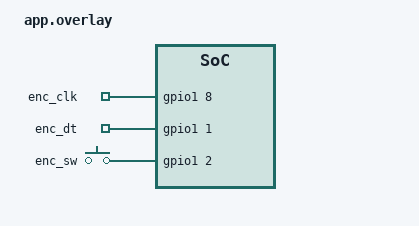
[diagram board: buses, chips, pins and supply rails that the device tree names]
/ {
    aliases {
        encoder-clk = &enc_clk;
        encoder-dt = &enc_dt;
        encoder-sw = &enc_sw;
    };

    encoder_pins {
        compatible = "gpio-keys";

        enc_clk: enc_clk {
            gpios = <&gpio1 8 (GPIO_ACTIVE_HIGH | GPIO_PULL_UP)>;
        };
        enc_dt: enc_dt {
            gpios = <&gpio1 1 (GPIO_ACTIVE_HIGH | GPIO_PULL_UP)>;
        };
        enc_sw: enc_sw {
            gpios = <&gpio1 2 (GPIO_ACTIVE_HIGH | GPIO_PULL_UP)>;
        };
    };
};
